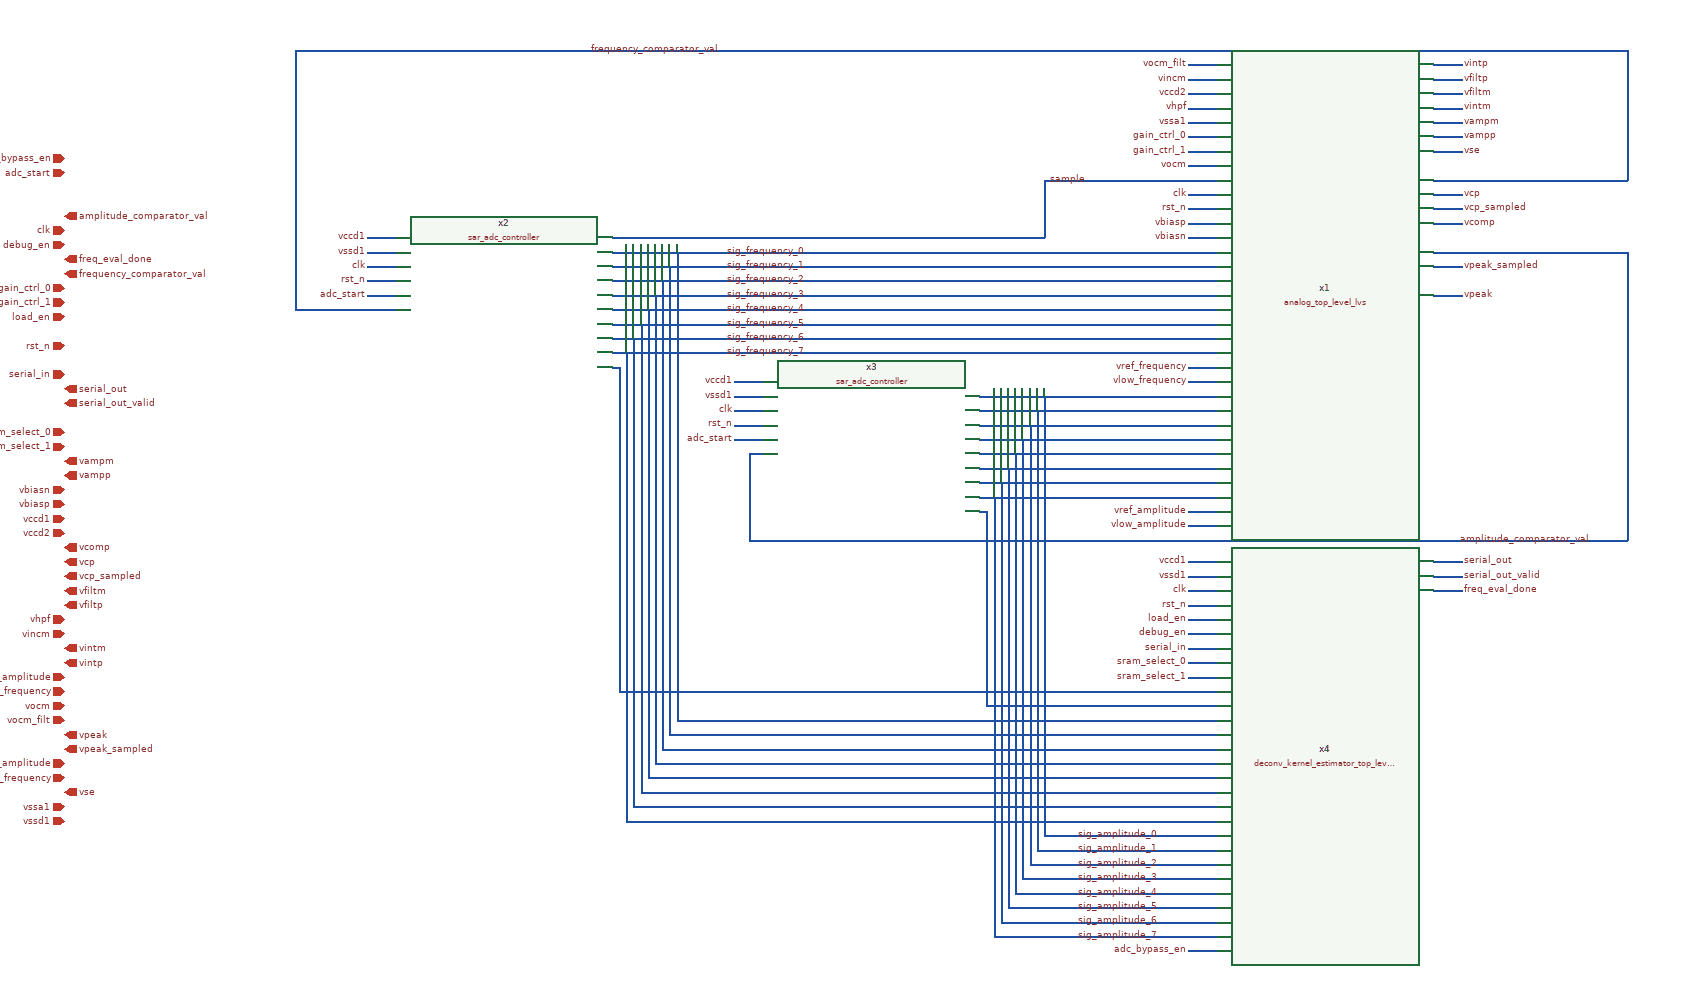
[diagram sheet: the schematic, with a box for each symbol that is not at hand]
v {xschem version=2.9.9 file_version=1.2 }
G {}
K {}
V {}
S {}
E {}
N 1850 -630 1890 -630 { lab=vlow_amplitude}
N 1850 -650 1890 -650 { lab=vref_amplitude}
N 1850 -830 1890 -830 { lab=vlow_frequency}
N 1850 -850 1890 -850 { lab=vref_frequency}
N 1850 -1030 1890 -1030 { lab=vbiasn}
N 1850 -1050 1890 -1050 { lab=vbiasp}
N 1850 -1130 1890 -1130 { lab=vocm}
N 1850 -1210 1890 -1210 { lab=vhpf}
N 1850 -1250 1890 -1250 { lab=vincm}
N 1850 -1270 1890 -1270 { lab=vocm_filt}
N 2190 -1270 2230 -1270 { lab=vfiltp}
N 2190 -1250 2230 -1250 { lab=vfiltp}
N 2190 -1230 2230 -1230 { lab=vfiltm}
N 2190 -1210 2230 -1210 { lab=vintm}
N 2190 -1190 2230 -1190 { lab=vampm}
N 2190 -1170 2230 -1170 { lab=vampp}
N 2190 -1150 2230 -1150 { lab=vse}
N 2190 -1090 2230 -1090 { lab=vcp}
N 2190 -1070 2230 -1070 { lab=vcp_sampled}
N 2190 -950 2230 -950 { lab=vpeak}
N 2190 -990 2230 -990 { lab=vpeak_sampled}
N 2190 -1050 2230 -1050 { lab=vcomp}
N 1850 -1170 1890 -1170 { lab=gain_ctrl_0}
N 1850 -1150 1890 -1150 { lab=gain_ctrl_1}
N 1850 -1110 1890 -1110 { lab=sample}
N 1850 -1090 1890 -1090 { lab=clk}
N 1850 -1230 1890 -1230 { lab=vccd2}
N 1850 -1190 1890 -1190 { lab=vssa1}
N 1650 -1110 1850 -1110 { lab=sample}
N 1050 -1010 1890 -1010 { lab=sig_frequency_0}
N 1580 -670 1580 -440 { lab=sig_amplitude_7}
N 1590 -690 1590 -450 { lab=sig_amplitude_6}
N 1600 -710 1600 -460 { lab=sig_amplitude_5}
N 1610 -730 1610 -470 { lab=sig_amplitude_4}
N 1620 -750 1620 -480 { lab=sig_amplitude_3}
N 1630 -770 1630 -490 { lab=sig_amplitude_2}
N 1640 -790 1640 -500 { lab=sig_amplitude_1}
N 1650 -810 1650 -510 { lab=sig_amplitude_0}
N 1650 -200 1890 -200 { lab=sig_amplitude_0}
N 1640 -180 1890 -180 { lab=sig_amplitude_1}
N 1630 -160 1890 -160 { lab=sig_amplitude_2}
N 1620 -140 1890 -140 { lab=sig_amplitude_3}
N 1610 -120 1890 -120 { lab=sig_amplitude_4}
N 1600 -100 1890 -100 { lab=sig_amplitude_5}
N 1590 -80 1890 -80 { lab=sig_amplitude_6}
N 1580 -60 1890 -60 { lab=sig_amplitude_7}
N 1560 -810 1890 -810 { lab=sig_amplitude_0}
N 1560 -790 1890 -790 { lab=sig_amplitude_1}
N 1560 -770 1890 -770 { lab=sig_amplitude_2}
N 1560 -750 1890 -750 { lab=sig_amplitude_3}
N 1560 -730 1890 -730 { lab=sig_amplitude_4}
N 1560 -710 1890 -710 { lab=sig_amplitude_5}
N 1560 -690 1890 -690 { lab=sig_amplitude_6}
N 1560 -670 1890 -670 { lab=sig_amplitude_7}
N 1650 -510 1650 -200 { lab=sig_amplitude_0}
N 1640 -500 1640 -180 { lab=sig_amplitude_1}
N 1630 -490 1630 -160 { lab=sig_amplitude_2}
N 1620 -480 1620 -140 { lab=sig_amplitude_3}
N 1610 -470 1610 -120 { lab=sig_amplitude_4}
N 1600 -460 1600 -100 { lab=sig_amplitude_5}
N 1590 -450 1590 -80 { lab=sig_amplitude_6}
N 1580 -440 1580 -60 { lab=sig_amplitude_7}
N 1070 -870 1070 -640 { lab=sig_frequency_7}
N 1080 -890 1080 -650 { lab=sig_frequency_6}
N 1090 -910 1090 -660 { lab=sig_frequency_5}
N 1100 -930 1100 -670 { lab=sig_frequency_4}
N 1110 -950 1110 -680 { lab=sig_frequency_3}
N 1120 -970 1120 -690 { lab=sig_frequency_2}
N 1130 -990 1130 -700 { lab=sig_frequency_1}
N 1140 -1010 1140 -710 { lab=sig_frequency_0}
N 1070 -220 1890 -220 { lab=sig_frequency_7}
N 1070 -640 1070 -220 { lab=sig_frequency_7}
N 1080 -650 1080 -240 { lab=sig_frequency_6}
N 1080 -240 1890 -240 { lab=sig_frequency_6}
N 1090 -260 1890 -260 { lab=sig_frequency_5}
N 1090 -660 1090 -260 { lab=sig_frequency_5}
N 1100 -670 1100 -280 { lab=sig_frequency_4}
N 1100 -280 1890 -280 { lab=sig_frequency_4}
N 1110 -300 1890 -300 { lab=sig_frequency_3}
N 1110 -680 1110 -300 { lab=sig_frequency_3}
N 1120 -690 1120 -320 { lab=sig_frequency_2}
N 1120 -320 1890 -320 { lab=sig_frequency_2}
N 1130 -340 1890 -340 { lab=sig_frequency_1}
N 1130 -700 1130 -340 { lab=sig_frequency_1}
N 1140 -710 1140 -360 { lab=sig_frequency_0}
N 1140 -360 1890 -360 { lab=sig_frequency_0}
N 1050 -990 1890 -990 { lab=sig_frequency_1}
N 1050 -970 1890 -970 { lab=sig_frequency_2}
N 1050 -950 1890 -950 { lab=sig_frequency_3}
N 1050 -930 1890 -930 { lab=sig_frequency_4}
N 1050 -910 1890 -910 { lab=sig_frequency_5}
N 1050 -890 1890 -890 { lab=sig_frequency_6}
N 1050 -870 1890 -870 { lab=sig_frequency_7}
N 1050 -1030 1650 -1030 { lab=sample}
N 1220 -830 1260 -830 { lab=vccd1}
N 1850 -580 1890 -580 { lab=vccd1}
N 710 -1030 750 -1030 { lab=vccd1}
N 710 -1010 750 -1010 { lab=vssd1}
N 1220 -810 1260 -810 { lab=vssd1}
N 1850 -560 1890 -560 { lab=vssd1}
N 1560 -650 1570 -650 { lab=#net1}
N 1570 -650 1570 -380 { lab=#net1}
N 1570 -380 1890 -380 { lab=#net1}
N 1050 -850 1060 -850 { lab=#net2}
N 1060 -400 1890 -400 { lab=#net2}
N 1060 -850 1060 -400 { lab=#net2}
N 1850 -440 1890 -440 { lab=sram_select_0}
N 1850 -420 1890 -420 { lab=sram_select_1}
N 1850 -540 1890 -540 { lab=clk}
N 1850 -520 1890 -520 { lab=rst_n}
N 710 -990 750 -990 { lab=clk}
N 710 -970 750 -970 { lab=rst_n}
N 1220 -790 1260 -790 { lab=clk}
N 1220 -770 1260 -770 { lab=rst_n}
N 710 -950 750 -950 { lab=adc_start}
N 1220 -750 1260 -750 { lab=adc_start}
N 610 -1290 2460 -1290 { lab=frequency_comparator_val}
N 610 -1290 610 -930 { lab=frequency_comparator_val}
N 610 -930 750 -930 { lab=frequency_comparator_val}
N 2460 -990 2460 -610 { lab=amplitude_comparator_val}
N 1240 -610 2460 -610 { lab=amplitude_comparator_val}
N 1240 -730 1240 -610 { lab=amplitude_comparator_val}
N 1240 -730 1260 -730 { lab=amplitude_comparator_val}
N 1850 -500 1890 -500 { lab=load_en}
N 1850 -480 1890 -480 { lab=debug_en}
N 1850 -460 1890 -460 { lab=serial_in}
N 2190 -580 2230 -580 { lab=serial_out}
N 2190 -560 2230 -560 { lab=serial_out_valid}
N 2190 -540 2230 -540 { lab=freq_eval_done}
N 1850 -40 1890 -40 { lab=adc_bypass_en}
N 1650 -1110 1650 -1090 { lab=sample}
N 1850 -1070 1890 -1070 { lab=rst_n}
N 2190 -1110 2460 -1110 { lab=frequency_comparator_val}
N 2460 -1290 2460 -1110 { lab=frequency_comparator_val}
N 2190 -1010 2460 -1010 { lab=amplitude_comparator_val}
N 2460 -1010 2460 -990 { lab=amplitude_comparator_val}
N 1650 -1090 1650 -1030 { lab=sample}
C {/home/users/nhpoole/ee272b/ee272b_mixed_signal_mmwave_accelerator/designs/analog_top_level_lvs.sym} 2040 -950 0 0 {name=x1}
C {devices/lab_pin.sym} 1850 -630 0 0 {name=l13 sig_type=std_logic lab=vlow_amplitude}
C {devices/lab_pin.sym} 1850 -650 0 0 {name=l14 sig_type=std_logic lab=vref_amplitude}
C {devices/lab_pin.sym} 1850 -830 0 0 {name=l15 sig_type=std_logic lab=vlow_frequency}
C {devices/lab_pin.sym} 1850 -850 0 0 {name=l16 sig_type=std_logic lab=vref_frequency}
C {devices/lab_pin.sym} 1850 -1030 0 0 {name=l17 sig_type=std_logic lab=vbiasn}
C {devices/lab_pin.sym} 1850 -1050 0 0 {name=l18 sig_type=std_logic lab=vbiasp}
C {devices/lab_pin.sym} 1850 -1130 0 0 {name=l19 sig_type=std_logic lab=vocm}
C {devices/lab_pin.sym} 1850 -1210 0 0 {name=l20 sig_type=std_logic lab=vhpf}
C {devices/lab_pin.sym} 1850 -1250 0 0 {name=l21 sig_type=std_logic lab=vincm}
C {devices/lab_pin.sym} 1850 -1270 0 0 {name=l22 sig_type=std_logic lab=vocm_filt}
C {devices/lab_pin.sym} 2230 -1270 0 1 {name=l23 sig_type=std_logic lab=vintp}
C {devices/lab_pin.sym} 2230 -1250 0 1 {name=l24 sig_type=std_logic lab=vfiltp}
C {devices/lab_pin.sym} 2230 -1230 0 1 {name=l25 sig_type=std_logic lab=vfiltm}
C {devices/lab_pin.sym} 2230 -1210 0 1 {name=l26 sig_type=std_logic lab=vintm}
C {devices/lab_pin.sym} 2230 -1190 0 1 {name=l27 sig_type=std_logic lab=vampm}
C {devices/lab_pin.sym} 2230 -1170 0 1 {name=l28 sig_type=std_logic lab=vampp}
C {devices/lab_pin.sym} 2230 -1150 0 1 {name=l31 sig_type=std_logic lab=vse}
C {devices/lab_pin.sym} 2230 -1090 0 1 {name=l32 sig_type=std_logic lab=vcp}
C {devices/lab_pin.sym} 2230 -1070 0 1 {name=l33 sig_type=std_logic lab=vcp_sampled}
C {devices/lab_pin.sym} 2230 -950 0 1 {name=l34 sig_type=std_logic lab=vpeak}
C {devices/lab_pin.sym} 2230 -990 0 1 {name=l35 sig_type=std_logic lab=vpeak_sampled}
C {devices/lab_pin.sym} 2230 -1050 0 1 {name=l36 sig_type=std_logic lab=vcomp}
C {devices/lab_pin.sym} 1850 -1170 0 0 {name=l40 sig_type=std_logic lab=gain_ctrl_0}
C {devices/lab_pin.sym} 1850 -1150 0 0 {name=l41 sig_type=std_logic lab=gain_ctrl_1}
C {devices/lab_pin.sym} 1850 -1090 0 0 {name=l43 sig_type=std_logic lab=clk}
C {devices/lab_pin.sym} 1850 -1230 0 0 {name=l7 sig_type=std_logic lab=vccd2}
C {devices/lab_pin.sym} 1850 -1190 0 0 {name=l8 sig_type=std_logic lab=vssa1}
C {/home/users/nhpoole/ee272b/ee272b_mixed_signal_mmwave_accelerator/designs/sar_adc_controller.sym} 900 -940 0 0 {name=x2}
C {/home/users/nhpoole/ee272b/ee272b_mixed_signal_mmwave_accelerator/designs/sar_adc_controller.sym} 1410 -740 0 0 {name=x3}
C {/home/users/nhpoole/ee272b/ee272b_mixed_signal_mmwave_accelerator/designs/deconv_kernel_estimator_top_level.sym} 2040 -310 0 0 {name=x4}
C {devices/lab_wire.sym} 1320 -1010 0 0 {name=l1 sig_type=std_logic lab=sig_frequency_0}
C {devices/lab_wire.sym} 1320 -990 0 0 {name=l2 sig_type=std_logic lab=sig_frequency_1}
C {devices/lab_wire.sym} 1320 -970 0 0 {name=l3 sig_type=std_logic lab=sig_frequency_2}
C {devices/lab_wire.sym} 1320 -950 0 0 {name=l4 sig_type=std_logic lab=sig_frequency_3}
C {devices/lab_wire.sym} 1320 -930 0 0 {name=l5 sig_type=std_logic lab=sig_frequency_4}
C {devices/lab_wire.sym} 1320 -910 0 0 {name=l6 sig_type=std_logic lab=sig_frequency_5}
C {devices/lab_wire.sym} 1320 -890 0 0 {name=l9 sig_type=std_logic lab=sig_frequency_6}
C {devices/lab_wire.sym} 1320 -870 0 0 {name=l10 sig_type=std_logic lab=sig_frequency_7}
C {devices/lab_wire.sym} 1710 -1110 0 0 {name=l42 sig_type=std_logic lab=sample}
C {devices/lab_wire.sym} 1810 -200 0 0 {name=l11 sig_type=std_logic lab=sig_amplitude_0}
C {devices/lab_wire.sym} 1810 -180 0 0 {name=l12 sig_type=std_logic lab=sig_amplitude_1}
C {devices/lab_wire.sym} 1810 -160 0 0 {name=l44 sig_type=std_logic lab=sig_amplitude_2}
C {devices/lab_wire.sym} 1810 -140 0 0 {name=l45 sig_type=std_logic lab=sig_amplitude_3}
C {devices/lab_wire.sym} 1810 -120 0 0 {name=l46 sig_type=std_logic lab=sig_amplitude_4}
C {devices/lab_wire.sym} 1810 -100 0 0 {name=l47 sig_type=std_logic lab=sig_amplitude_5}
C {devices/lab_wire.sym} 1810 -80 0 0 {name=l48 sig_type=std_logic lab=sig_amplitude_6}
C {devices/lab_wire.sym} 1810 -60 0 0 {name=l49 sig_type=std_logic lab=sig_amplitude_7}
C {devices/noconn.sym} 1560 -830 0 1 {name=l50}
C {devices/lab_pin.sym} 1220 -830 0 0 {name=l51 sig_type=std_logic lab=vccd1}
C {devices/lab_pin.sym} 1850 -580 0 0 {name=l52 sig_type=std_logic lab=vccd1}
C {devices/lab_pin.sym} 710 -1030 0 0 {name=l53 sig_type=std_logic lab=vccd1}
C {devices/lab_pin.sym} 710 -1010 0 0 {name=l54 sig_type=std_logic lab=vssd1}
C {devices/lab_pin.sym} 1220 -810 0 0 {name=l55 sig_type=std_logic lab=vssd1}
C {devices/lab_pin.sym} 1850 -560 0 0 {name=l56 sig_type=std_logic lab=vssd1}
C {devices/lab_pin.sym} 1850 -440 0 0 {name=l57 sig_type=std_logic lab=sram_select_0}
C {devices/lab_pin.sym} 1850 -420 0 0 {name=l58 sig_type=std_logic lab=sram_select_1}
C {devices/lab_pin.sym} 1850 -540 0 0 {name=l59 sig_type=std_logic lab=clk}
C {devices/lab_pin.sym} 1850 -520 0 0 {name=l60 sig_type=std_logic lab=rst_n}
C {devices/lab_pin.sym} 710 -990 0 0 {name=l61 sig_type=std_logic lab=clk}
C {devices/lab_pin.sym} 710 -970 0 0 {name=l62 sig_type=std_logic lab=rst_n}
C {devices/lab_pin.sym} 1220 -790 0 0 {name=l63 sig_type=std_logic lab=clk}
C {devices/lab_pin.sym} 1220 -770 0 0 {name=l64 sig_type=std_logic lab=rst_n}
C {devices/lab_pin.sym} 710 -950 0 0 {name=l65 sig_type=std_logic lab=adc_start}
C {devices/lab_pin.sym} 1220 -750 0 0 {name=l66 sig_type=std_logic lab=adc_start}
C {devices/lab_wire.sym} 1200 -1290 0 0 {name=l37 sig_type=std_logic lab=frequency_comparator_val}
C {devices/lab_wire.sym} 2410 -610 0 0 {name=l38 sig_type=std_logic lab=amplitude_comparator_val}
C {devices/lab_pin.sym} 1850 -500 0 0 {name=l67 sig_type=std_logic lab=load_en}
C {devices/lab_pin.sym} 1850 -480 0 0 {name=l68 sig_type=std_logic lab=debug_en}
C {devices/lab_pin.sym} 1850 -460 0 0 {name=l69 sig_type=std_logic lab=serial_in}
C {devices/lab_pin.sym} 2230 -580 0 1 {name=l70 sig_type=std_logic lab=serial_out}
C {devices/lab_pin.sym} 2230 -560 0 1 {name=l71 sig_type=std_logic lab=serial_out_valid}
C {devices/lab_pin.sym} 2230 -540 0 1 {name=l72 sig_type=std_logic lab=freq_eval_done}
C {devices/lab_pin.sym} 1850 -40 0 0 {name=l73 sig_type=std_logic lab=adc_bypass_en}
C {devices/ipin.sym} 290 -220 0 0 { name=p1 lab=vssd1 }
C {devices/ipin.sym} 290 -240 0 0 { name=p2 lab=vssa1 }
C {devices/opin.sym} 290 -260 0 0 { name=p3 lab=vse }
C {devices/ipin.sym} 290 -280 0 0 { name=p4 lab=vref_frequency }
C {devices/ipin.sym} 290 -300 0 0 { name=p5 lab=vref_amplitude }
C {devices/opin.sym} 290 -320 0 0 { name=p6 lab=vpeak_sampled }
C {devices/opin.sym} 290 -340 0 0 { name=p7 lab=vpeak }
C {devices/ipin.sym} 290 -360 0 0 { name=p8 lab=vocm_filt }
C {devices/ipin.sym} 290 -380 0 0 { name=p9 lab=vocm }
C {devices/ipin.sym} 290 -400 0 0 { name=p10 lab=vlow_frequency }
C {devices/ipin.sym} 290 -420 0 0 { name=p11 lab=vlow_amplitude }
C {devices/opin.sym} 290 -440 0 0 { name=p12 lab=vintp }
C {devices/opin.sym} 290 -460 0 0 { name=p13 lab=vintm }
C {devices/ipin.sym} 290 -480 0 0 { name=p14 lab=vincm }
C {devices/ipin.sym} 290 -500 0 0 { name=p15 lab=vhpf }
C {devices/opin.sym} 290 -520 0 0 { name=p16 lab=vfiltp }
C {devices/opin.sym} 290 -540 0 0 { name=p17 lab=vfiltm }
C {devices/opin.sym} 290 -560 0 0 { name=p18 lab=vcp_sampled }
C {devices/opin.sym} 290 -580 0 0 { name=p19 lab=vcp }
C {devices/opin.sym} 290 -600 0 0 { name=p20 lab=vcomp }
C {devices/ipin.sym} 290 -620 0 0 { name=p21 lab=vccd2 }
C {devices/ipin.sym} 290 -640 0 0 { name=p22 lab=vccd1 }
C {devices/ipin.sym} 290 -660 0 0 { name=p23 lab=vbiasp }
C {devices/ipin.sym} 290 -680 0 0 { name=p24 lab=vbiasn }
C {devices/opin.sym} 290 -700 0 0 { name=p25 lab=vampp }
C {devices/opin.sym} 290 -720 0 0 { name=p26 lab=vampm }
C {devices/ipin.sym} 290 -740 0 0 { name=p27 lab=sram_select_1}
C {devices/opin.sym} 290 -800 0 0 { name=p30 lab=serial_out_valid }
C {devices/opin.sym} 290 -820 0 0 { name=p31 lab=serial_out }
C {devices/ipin.sym} 290 -840 0 0 { name=p32 lab=serial_in }
C {devices/ipin.sym} 290 -880 0 0 { name=p34 lab=rst_n }
C {devices/ipin.sym} 290 -920 0 0 { name=p36 lab=load_en }
C {devices/ipin.sym} 290 -940 0 0 { name=p37 lab=gain_ctrl_1 }
C {devices/ipin.sym} 290 -960 0 0 { name=p38 lab=gain_ctrl_0 }
C {devices/opin.sym} 290 -980 0 0 { name=p39 lab=frequency_comparator_val }
C {devices/opin.sym} 290 -1000 0 0 { name=p40 lab=freq_eval_done }
C {devices/ipin.sym} 290 -1020 0 0 { name=p41 lab=debug_en }
C {devices/ipin.sym} 290 -1040 0 0 { name=p42 lab=clk }
C {devices/opin.sym} 290 -1060 0 0 { name=p43 lab=amplitude_comparator_val }
C {devices/ipin.sym} 290 -1120 0 0 { name=p46 lab=adc_start }
C {devices/ipin.sym} 290 -1140 0 0 { name=p47 lab=adc_bypass_en }
C {devices/noconn.sym} 2190 -1130 0 1 {name=l29}
C {devices/noconn.sym} 2190 -1030 0 1 {name=l30}
C {devices/ipin.sym} 290 -760 0 0 { name=p28 lab=sram_select_0}
C {devices/lab_pin.sym} 1850 -1070 0 0 {name=l74 sig_type=std_logic lab=rst_n}
C {devices/noconn.sym} 2190 -970 0 1 {name=l39}
